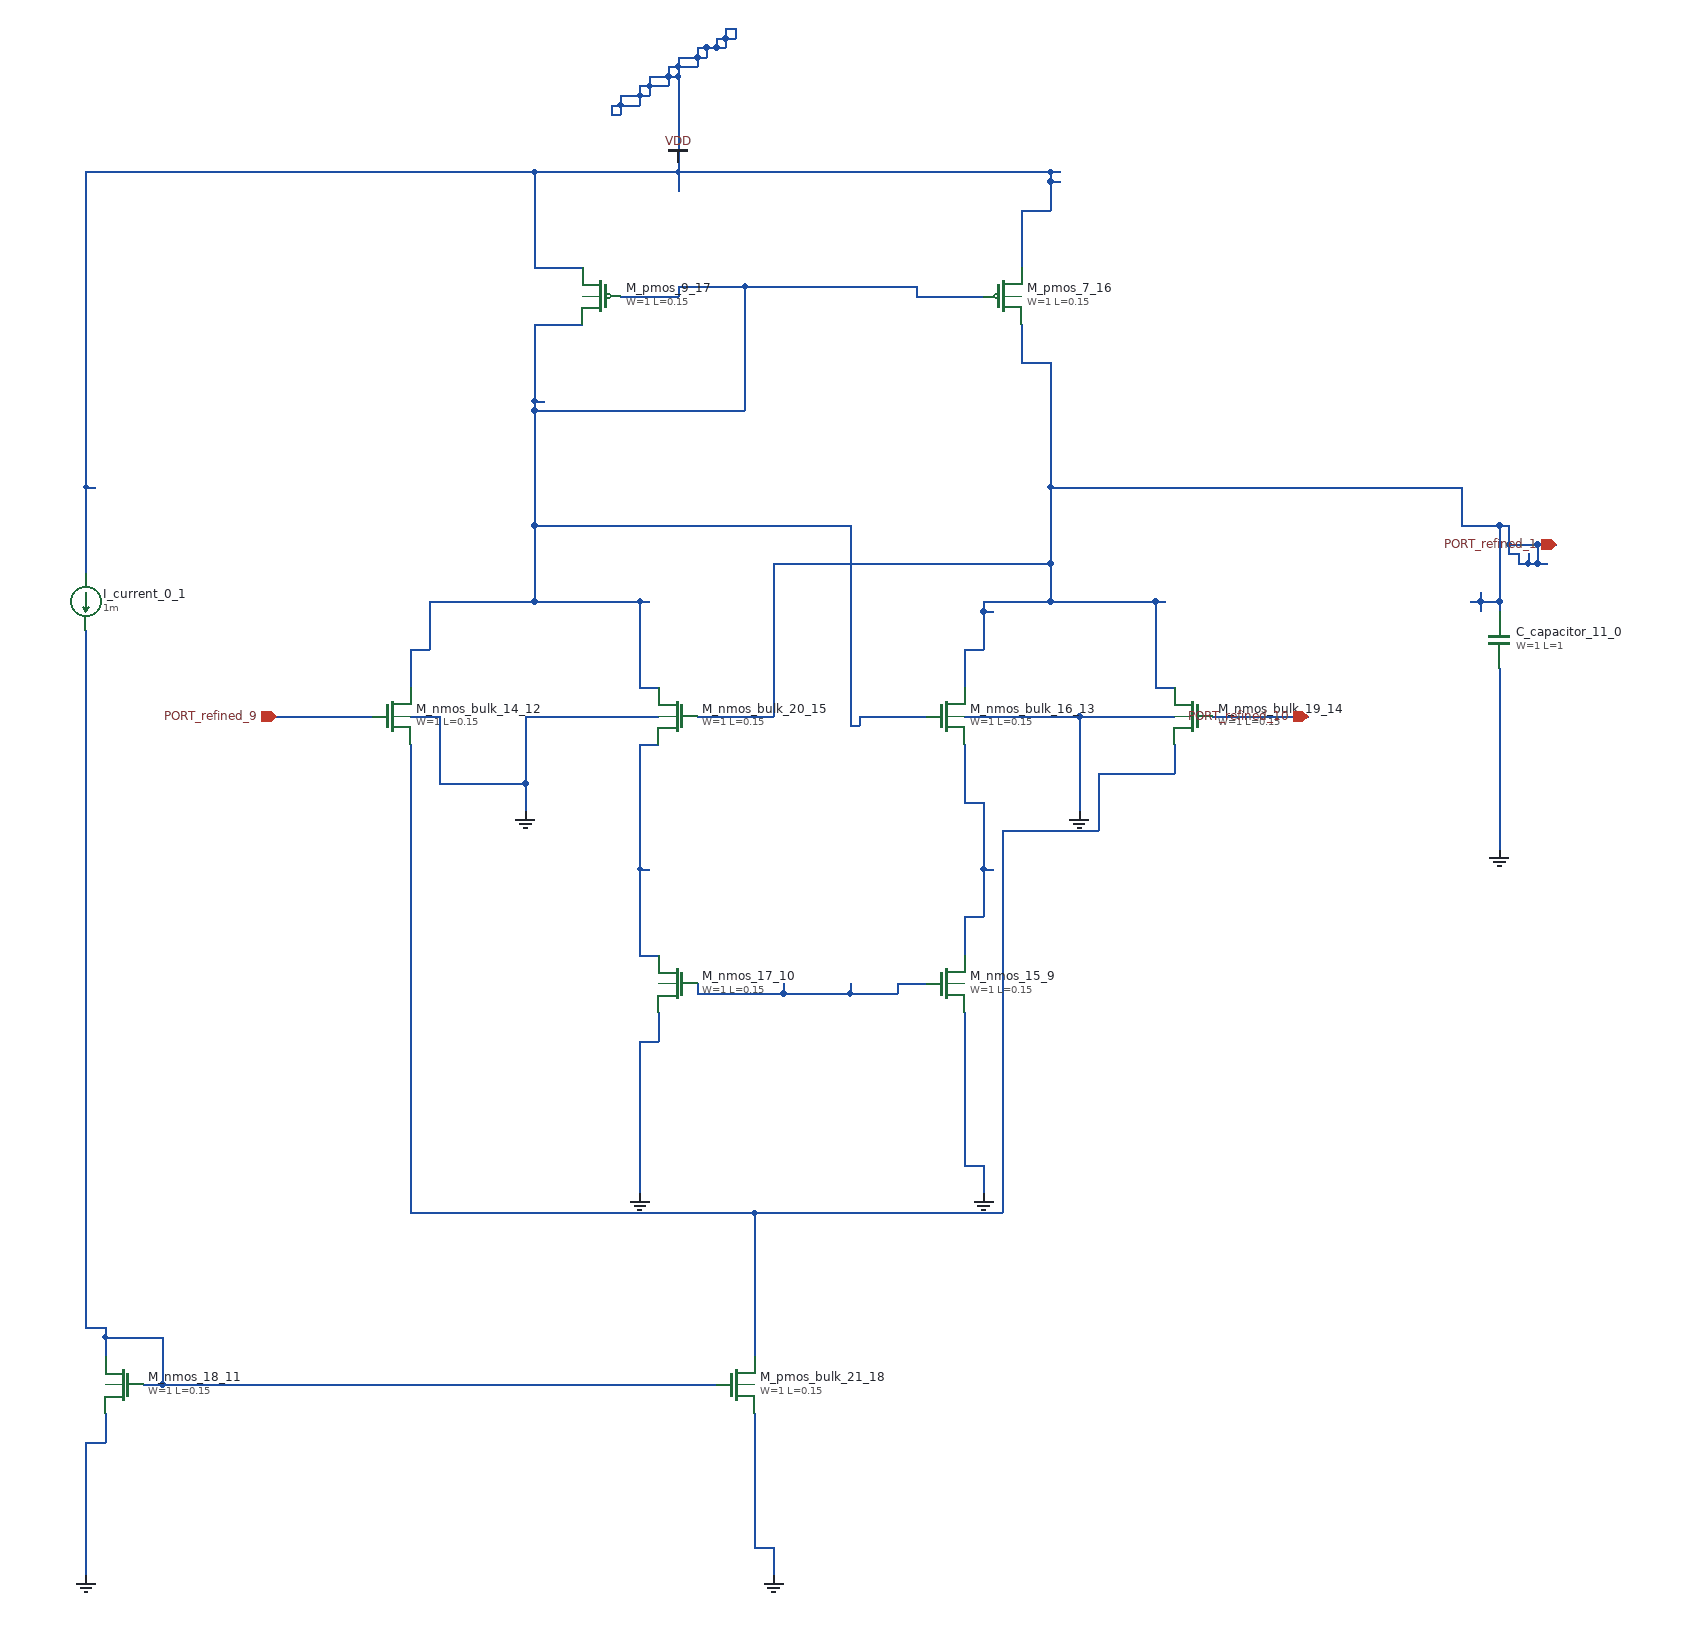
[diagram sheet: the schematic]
v {xschem version=3.4.8 file_version=1.2}
G {}
K {}
V {}
S {}
E {}
C {sky130_fd_pr/cap_mim_m3_1.sym} 1700 700 0 0 {name="C_capacitor_11_0" model=cap_mim_m3_1 W=1 L=1 MF=1 spiceprefix=X}
C {devices/isource.sym} 220 660 0 0 {name="I_current_0_1" value=1m}
C {devices/gnd.sym} 680 880 0 0 {name="l_gnd_1_2" lab="GND"}
C {devices/gnd.sym} 1260 880 0 0 {name="l_gnd_12_3" lab="GND"}
C {devices/gnd.sym} 1160 1280 0 0 {name="l_gnd_2_4" lab="GND"}
C {devices/gnd.sym} 800 1280 0 0 {name="l_gnd_3_5" lab="GND"}
C {devices/gnd.sym} 940 1680 0 0 {name="l_gnd_4_6" lab="GND"}
C {devices/gnd.sym} 220 1680 0 0 {name="l_gnd_5_7" lab="GND"}
C {devices/gnd.sym} 1700 920 0 0 {name="l_gnd_6_8" lab="GND"}
C {sky130_fd_pr/nfet3_01v8.sym} 1120 1060 0 0 {name="M_nmos_15_9"
W=1
L=0.15
body=GND
nf=1
mult=1
ad="expr('int((@nf + 1)/2) * @W / @nf * 0.29')"
pd="expr('2*int((@nf + 1)/2) * (@W / @nf + 0.29)')"
as="expr('int((@nf + 2)/2) * @W / @nf * 0.29')"
ps="expr('2*int((@nf + 2)/2) * (@W / @nf + 0.29)')"
nrd="expr('0.29 / @W ')" nrs="expr('0.29 / @W ')"
sa=0 sb=0 sd=0
model=nfet_01v8
spiceprefix=X
}
C {sky130_fd_pr/nfet3_01v8.sym} 840 1060 0 1 {name="M_nmos_17_10"
W=1
L=0.15
body=GND
nf=1
mult=1
ad="expr('int((@nf + 1)/2) * @W / @nf * 0.29')"
pd="expr('2*int((@nf + 1)/2) * (@W / @nf + 0.29)')"
as="expr('int((@nf + 2)/2) * @W / @nf * 0.29')"
ps="expr('2*int((@nf + 2)/2) * (@W / @nf + 0.29)')"
nrd="expr('0.29 / @W ')" nrs="expr('0.29 / @W ')"
sa=0 sb=0 sd=0
model=nfet_01v8
spiceprefix=X
}
C {sky130_fd_pr/nfet3_01v8.sym} 260 1480 0 1 {name="M_nmos_18_11"
W=1
L=0.15
body=GND
nf=1
mult=1
ad="expr('int((@nf + 1)/2) * @W / @nf * 0.29')"
pd="expr('2*int((@nf + 1)/2) * (@W / @nf + 0.29)')"
as="expr('int((@nf + 2)/2) * @W / @nf * 0.29')"
ps="expr('2*int((@nf + 2)/2) * (@W / @nf + 0.29)')"
nrd="expr('0.29 / @W ')" nrs="expr('0.29 / @W ')"
sa=0 sb=0 sd=0
model=nfet_01v8
spiceprefix=X
}
C {sky130_fd_pr/nfet_01v8.sym} 540 780 0 0 {name="M_nmos_bulk_14_12"
W=1
L=0.15
nf=1 
mult=1
ad="expr('int((@nf + 1)/2) * @W / @nf * 0.29')"
pd="expr('2*int((@nf + 1)/2) * (@W / @nf + 0.29)')"
as="expr('int((@nf + 2)/2) * @W / @nf * 0.29')"
ps="expr('2*int((@nf + 2)/2) * (@W / @nf + 0.29)')"
nrd="expr('0.29 / @W ')" nrs="expr('0.29 / @W ')"
sa=0 sb=0 sd=0
model=nfet_01v8
spiceprefix=X
}
C {sky130_fd_pr/nfet_01v8.sym} 1120 780 0 0 {name="M_nmos_bulk_16_13"
W=1
L=0.15
nf=1 
mult=1
ad="expr('int((@nf + 1)/2) * @W / @nf * 0.29')"
pd="expr('2*int((@nf + 1)/2) * (@W / @nf + 0.29)')"
as="expr('int((@nf + 2)/2) * @W / @nf * 0.29')"
ps="expr('2*int((@nf + 2)/2) * (@W / @nf + 0.29)')"
nrd="expr('0.29 / @W ')" nrs="expr('0.29 / @W ')"
sa=0 sb=0 sd=0
model=nfet_01v8
spiceprefix=X
}
C {sky130_fd_pr/nfet_01v8.sym} 1380 780 0 1 {name="M_nmos_bulk_19_14"
W=1
L=0.15
nf=1 
mult=1
ad="expr('int((@nf + 1)/2) * @W / @nf * 0.29')"
pd="expr('2*int((@nf + 1)/2) * (@W / @nf + 0.29)')"
as="expr('int((@nf + 2)/2) * @W / @nf * 0.29')"
ps="expr('2*int((@nf + 2)/2) * (@W / @nf + 0.29)')"
nrd="expr('0.29 / @W ')" nrs="expr('0.29 / @W ')"
sa=0 sb=0 sd=0
model=nfet_01v8
spiceprefix=X
}
C {sky130_fd_pr/nfet_01v8.sym} 840 780 0 1 {name="M_nmos_bulk_20_15"
W=1
L=0.15
nf=1 
mult=1
ad="expr('int((@nf + 1)/2) * @W / @nf * 0.29')"
pd="expr('2*int((@nf + 1)/2) * (@W / @nf + 0.29)')"
as="expr('int((@nf + 2)/2) * @W / @nf * 0.29')"
ps="expr('2*int((@nf + 2)/2) * (@W / @nf + 0.29)')"
nrd="expr('0.29 / @W ')" nrs="expr('0.29 / @W ')"
sa=0 sb=0 sd=0
model=nfet_01v8
spiceprefix=X
}
C {sky130_fd_pr/pfet3_01v8.sym} 1180 340 0 0 {name="M_pmos_7_16"
W=1
L=0.15
body=VDD
nf=1
mult=1
ad="expr('int((@nf + 1)/2) * @W / @nf * 0.29')"
pd="expr('2*int((@nf + 1)/2) * (@W / @nf + 0.29)')"
as="expr('int((@nf + 2)/2) * @W / @nf * 0.29')"
ps="expr('2*int((@nf + 2)/2) * (@W / @nf + 0.29)')"
nrd="expr('0.29 / @W ')" nrs="expr('0.29 / @W ')"
sa=0 sb=0 sd=0
model=pfet_01v8
spiceprefix=X
}
C {sky130_fd_pr/pfet3_01v8.sym} 760 340 0 1 {name="M_pmos_9_17"
W=1
L=0.15
body=VDD
nf=1
mult=1
ad="expr('int((@nf + 1)/2) * @W / @nf * 0.29')"
pd="expr('2*int((@nf + 1)/2) * (@W / @nf + 0.29)')"
as="expr('int((@nf + 2)/2) * @W / @nf * 0.29')"
ps="expr('2*int((@nf + 2)/2) * (@W / @nf + 0.29)')"
nrd="expr('0.29 / @W ')" nrs="expr('0.29 / @W ')"
sa=0 sb=0 sd=0
model=pfet_01v8
spiceprefix=X
}
C {sky130_fd_pr/nfet3_01v8.sym} 900 1480 0 0 {name="M_pmos_bulk_21_18"
W=1
L=0.15
body=GND
nf=1
mult=1
ad="expr('int((@nf + 1)/2) * @W / @nf * 0.29')"
pd="expr('2*int((@nf + 1)/2) * (@W / @nf + 0.29)')"
as="expr('int((@nf + 2)/2) * @W / @nf * 0.29')"
ps="expr('2*int((@nf + 2)/2) * (@W / @nf + 0.29)')"
nrd="expr('0.29 / @W ')" nrs="expr('0.29 / @W ')"
sa=0 sb=0 sd=0
model=nfet_01v8
spiceprefix=X
}
C {devices/ipin.sym} 420 780 0 0 {name="p_port_10_19" lab="PORT_refined_9"}
C {devices/ipin.sym} 1760 600 0 0 {name="p_port_13_20" lab="PORT_refined_1"}
C {devices/ipin.sym} 1500 780 0 0 {name="p_port_8_21" lab="PORT_refined_10"}
C {devices/vdd.sym} 840 200 0 0 {name="l_vdd_22_22" lab="VDD"}
N 920 1650 940 1650 {}
N 220 1540 240 1540 {}
N 1140 1250 1160 1250 {}
N 800 1120 820 1120 {}
N 590 850 680 850 {}
N 560 780 590 780 {}
N 680 780 820 780 {}
N 1140 780 1260 780 {}
N 1260 780 1360 780 {}
N 220 1680 220 1540 {}
N 240 1540 240 1510 {}
N 590 850 590 780 {}
N 680 880 680 850 {}
N 680 850 680 780 {}
N 800 1280 800 1120 {}
N 820 1120 820 1090 {}
N 920 1650 920 1510 {}
N 940 1680 940 1650 {}
N 1140 1250 1140 1090 {}
N 1160 1280 1160 1250 {}
N 1260 880 1260 780 {}
N 1700 920 1700 730 {}
N 860 780 940 780 {}
N 1340 750 1360 750 {}
N 1140 710 1160 710 {}
N 1160 670 1170 670 {}
N 1160 660 1230 660 {}
N 1230 660 1340 660 {}
N 1340 660 1350 660 {}
N 1670 660 1680 660 {}
N 1680 660 1700 660 {}
N 940 620 1230 620 {}
N 1720 620 1730 620 {}
N 1730 620 1740 620 {}
N 1740 620 1750 620 {}
N 1710 610 1720 610 {}
N 1710 600 1740 600 {}
N 1740 600 1760 600 {}
N 1660 580 1700 580 {}
N 1700 580 1710 580 {}
N 1230 540 1660 540 {}
N 1200 410 1230 410 {}
N 940 780 940 620 {}
N 1140 750 1140 710 {}
N 1160 710 1160 670 {}
N 1160 670 1160 660 {}
N 1200 410 1200 370 {}
N 1230 660 1230 620 {}
N 1230 620 1230 540 {}
N 1230 540 1230 410 {}
N 1340 750 1340 660 {}
N 1660 580 1660 540 {}
N 1680 670 1680 660 {}
N 1680 660 1680 650 {}
N 1700 670 1700 660 {}
N 1700 660 1700 580 {}
N 1710 610 1710 600 {}
N 1710 600 1710 580 {}
N 1720 620 1720 610 {}
N 1730 620 1730 610 {}
N 1740 620 1740 600 {}
N 1400 780 1500 780 {}
N 1140 990 1160 990 {}
N 1160 940 1170 940 {}
N 1140 870 1160 870 {}
N 1140 1030 1140 990 {}
N 1140 870 1140 810 {}
N 1160 990 1160 940 {}
N 1160 940 1160 870 {}
N 860 1070 950 1070 {}
N 950 1070 1020 1070 {}
N 1020 1070 1070 1070 {}
N 1070 1060 1100 1060 {}
N 860 1070 860 1060 {}
N 950 1070 950 1060 {}
N 1020 1070 1020 1060 {}
N 1070 1070 1070 1060 {}
N 800 1030 820 1030 {}
N 800 940 810 940 {}
N 800 810 820 810 {}
N 800 1030 800 940 {}
N 800 940 800 810 {}
N 280 1480 300 1480 {}
N 300 1480 880 1480 {}
N 240 1430 300 1430 {}
N 220 1420 240 1420 {}
N 220 1420 220 690 {}
N 240 1450 240 1430 {}
N 240 1430 240 1420 {}
N 300 1480 300 1430 {}
N 220 540 230 540 {}
N 690 310 740 310 {}
N 1200 250 1230 250 {}
N 1230 220 1240 220 {}
N 220 210 690 210 {}
N 690 210 840 210 {}
N 840 210 1230 210 {}
N 1230 210 1240 210 {}
N 770 150 780 150 {}
N 770 140 780 140 {}
N 780 140 800 140 {}
N 780 130 800 130 {}
N 800 130 810 130 {}
N 800 120 810 120 {}
N 810 120 830 120 {}
N 810 110 830 110 {}
N 830 110 840 110 {}
N 830 100 840 100 {}
N 840 100 860 100 {}
N 840 90 860 90 {}
N 860 90 870 90 {}
N 860 80 870 80 {}
N 870 80 880 80 {}
N 880 80 890 80 {}
N 880 70 890 70 {}
N 890 70 900 70 {}
N 890 60 900 60 {}
N 220 630 220 540 {}
N 220 540 220 210 {}
N 690 310 690 210 {}
N 770 150 770 140 {}
N 780 150 780 140 {}
N 780 140 780 130 {}
N 800 140 800 130 {}
N 800 130 800 120 {}
N 810 130 810 120 {}
N 810 120 810 110 {}
N 830 120 830 110 {}
N 830 110 830 100 {}
N 840 230 840 210 {}
N 840 210 840 200 {}
N 840 200 840 110 {}
N 840 110 840 100 {}
N 840 100 840 90 {}
N 860 100 860 90 {}
N 860 90 860 80 {}
N 870 90 870 80 {}
N 880 80 880 70 {}
N 890 80 890 70 {}
N 890 70 890 60 {}
N 900 70 900 60 {}
N 1200 310 1200 250 {}
N 1230 250 1230 220 {}
N 1230 220 1230 210 {}
N 1020 790 1030 790 {}
N 1030 780 1100 780 {}
N 800 750 820 750 {}
N 560 710 580 710 {}
N 580 660 690 660 {}
N 690 660 800 660 {}
N 800 660 810 660 {}
N 690 580 1020 580 {}
N 690 460 910 460 {}
N 690 450 700 450 {}
N 690 370 740 370 {}
N 780 340 840 340 {}
N 1090 340 1160 340 {}
N 840 330 910 330 {}
N 910 330 1090 330 {}
N 560 750 560 710 {}
N 580 710 580 660 {}
N 690 660 690 580 {}
N 690 580 690 460 {}
N 690 460 690 450 {}
N 690 450 690 370 {}
N 800 750 800 660 {}
N 840 340 840 330 {}
N 910 460 910 330 {}
N 1020 790 1020 580 {}
N 1030 790 1030 780 {}
N 1090 340 1090 330 {}
N 560 1300 920 1300 {}
N 920 1300 1180 1300 {}
N 1180 900 1280 900 {}
N 1280 840 1360 840 {}
N 560 1300 560 810 {}
N 920 1450 920 1300 {}
N 1180 1300 1180 900 {}
N 1280 900 1280 840 {}
N 1360 840 1360 810 {}
N 420 780 520 780 {}
